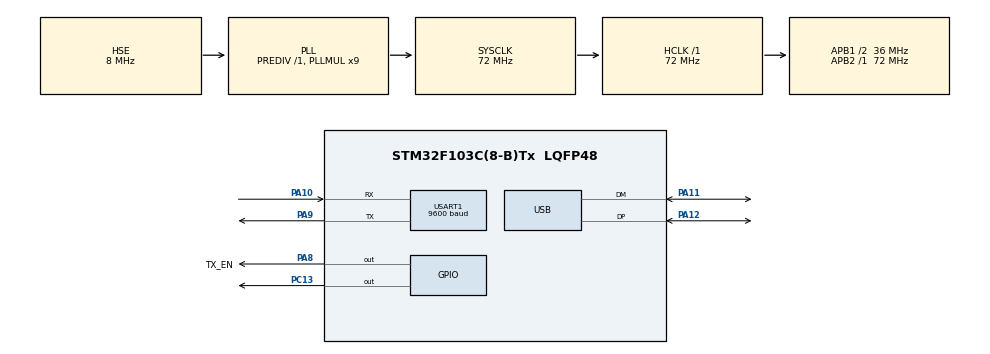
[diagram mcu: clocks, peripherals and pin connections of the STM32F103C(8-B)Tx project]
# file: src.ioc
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Mcu.Family=STM32F1
Mcu.Name=STM32F103C(8-B)Tx
Mcu.Package=LQFP48
NVIC.PriorityGroup=NVIC_PRIORITYGROUP_4
NVIC.USART1_IRQn=true\:0\:0\:false\:false\:true\:true\:true\:true
NVIC.USB_LP_CAN1_RX0_IRQn=true\:0\:0\:false\:false\:true\:false\:true\:true
PA10.Mode=Asynchronous
PA10.Signal=USART1_RX
PA11.Mode=Device
PA11.Signal=USB_DM
PA12.Mode=Device
PA12.Signal=USB_DP
PA13.Mode=Serial_Wire
PA13.Signal=SYS_JTMS-SWDIO
PA14.Mode=Serial_Wire
PA14.Signal=SYS_JTCK-SWCLK
PA8.GPIO_Label=TX_EN
PA8.Signal=GPIO_Output
PA9.Mode=Asynchronous
PA9.Signal=USART1_TX
PC13-TAMPER-RTC.Signal=GPIO_Output
PD0-OSC_IN.Mode=HSE-External-Oscillator
PD0-OSC_IN.Signal=RCC_OSC_IN
PD1-OSC_OUT.Mode=HSE-External-Oscillator
PD1-OSC_OUT.Signal=RCC_OSC_OUT
ProjectManager.HeapSize=0x200
ProjectManager.StackSize=0x400
ProjectManager.TargetToolchain=EWARM V8.32
RCC.AHBFreq_Value=72000000
RCC.APB1CLKDivider=RCC_HCLK_DIV2
RCC.APB1Freq_Value=36000000
RCC.APB1TimFreq_Value=72000000
RCC.APB2Freq_Value=72000000
RCC.APB2TimFreq_Value=72000000
RCC.HCLKFreq_Value=72000000
RCC.PLLMUL=RCC_PLL_MUL9
RCC.SYSCLKFreq_VALUE=72000000
RCC.SYSCLKSource=RCC_SYSCLKSOURCE_PLLCLK
RCC.USBFreq_Value=48000000
RCC.USBPrescaler=RCC_USBCLKSOURCE_PLL_DIV1_5
USART1.BaudRate=9600
USART1.VirtualMode=VM_ASYNC
USB_DEVICE.CLASS_NAME_FS=CDC
USB_DEVICE.VirtualMode=Cdc
USB_DEVICE.VirtualModeFS=Cdc_FS
VP_USB_DEVICE_VS_USB_DEVICE_CDC_FS.Mode=CDC_FS
board=custom

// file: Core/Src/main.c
/* USER CODE BEGIN Header */
/**
  ******************************************************************************
  * @file           : main.c
  * @brief          : Main program body
  ******************************************************************************
  * @attention
  *
  * Copyright (c) 2022 STMicroelectronics.
  * All rights reserved.
  *
  * This software is licensed under terms that can be found in the LICENSE file
  * in the root directory of this software component.
  * If no LICENSE file comes with this software, it is provided  AS-IS.
  *
  ******************************************************************************
  */
/* USER CODE END Header */
#include "main.h"
#include "usb_device.h"
/* USER CODE BEGIN Includes */
#include "usbd_core.h"
#include "usbd_cdc_if.h"
#include "modbus_crc.h"
#include "mbus_funcs.h"
/* USER CODE END Includes */

UART_HandleTypeDef huart1;

/* USER CODE BEGIN 0 */
void SystemClock_Config(void);
static void MX_GPIO_Init(void);
static void MX_USART1_UART_Init(void);
extern USBD_HandleTypeDef hUsbDeviceFS;

/* USER CODE END 0 */

int main(void)
{

  /* MCU Configuration--------------------------------------------------------*/

  /* Reset of all peripherals, Initializes the Flash interface and the Systick. */
  HAL_Init();

  /* Configure the system clock */
  SystemClock_Config();

  /* Initialize all configured peripherals */
  MX_GPIO_Init();
  MX_USB_DEVICE_Init();
  MX_USART1_UART_Init();
  /* USER CODE BEGIN 2 */

//Funciones ejemplo ModBUS

//readCoils(address, posicion, cantidad de coils);
  //readCoils(0x0001, 0, 1); // Example: Read 1 coils starting from position 0 of slave with address 1

//writeSingleCoil(address, posicion, valor);
  //writeSingleCoil(0x0001, 0, 1); // Example: Write value 1 (ON) to coil at position 0 of slave with address 1

//readInputContacts(address, posicion, cantidad de contactos);
  //readInputContacts(0x0001, 0, 10); // Example: Read 10 input contacts starting from position 0 of slave with address 1

//writeSingleRegister(address, posicion, valor);
  //writeSingleRegister(0x0001, 0, 123); // Example: Write value 123 to register at position 0 of slave with address 1

//writeMultipleRegisters(address, posicion, *datos, cantidad de datos);
//uint16_t datos[2] = {123, 456};
//writeMultipleRegisters(0x0001, 3, datos, 2);

//readHoldingRegisters(address, posicion, cantidad de datos);
  readHoldingRegisters(0x0001, 3, 2); // Example: Read registers at positions 6 and 7 of slave with address 1
  //readAnalogInputs(address, posicion, cantidad de datos);
  //readAnalogInputs(0x0001, 0, 2); // Example: Read analog inputs at positions 0 and 1 of slave with address 1

  /* USER CODE END 2 */

  /* Infinite loop */
  /* USER CODE BEGIN WHILE */
  while (1)
  {
    /* Button detection: PA0 press triggers Modbus read without reset */
    static uint8_t last_btn = 0;
    uint8_t btn = (HAL_GPIO_ReadPin(GPIOB, GPIO_PIN_10) == GPIO_PIN_SET) ? 1 : 0;
    if (btn && !last_btn) {
      HAL_Delay(20); /* debounce */
      if (HAL_GPIO_ReadPin(GPIOB, GPIO_PIN_10) == GPIO_PIN_SET) {
        readHoldingRegisters(0x0001, 3, 2);
      }
    }
    last_btn = btn;

    /* If UART callback marked data ready, try sending over USB when configured. */
    if (usb_data_ready)
    {
      if (hUsbDeviceFS.dev_state == USBD_STATE_CONFIGURED)
      {
        if (usb_buffer_len < sizeof(usb_buffer))
        {
          usb_buffer[usb_buffer_len++] = '\n';
        }

        uint8_t res = CDC_Transmit_FS(usb_buffer, usb_buffer_len);
        if (res == USBD_OK)
        {
          usb_data_ready = 0; // sent
        }
        else if (res == USBD_BUSY)
        {
          /* Host busy — keep flag set and retry next loop */
        }
        else
        {
          /* On error, drop the data to avoid lock — you can implement retries */
          usb_data_ready = 0;
        }
      }
    }

    HAL_Delay(10);
  }

    /* USER CODE END WHILE */

  /* USER CODE END 3 */
}

void SystemClock_Config(void)
{
  RCC_OscInitTypeDef RCC_OscInitStruct = {0};
  RCC_ClkInitTypeDef RCC_ClkInitStruct = {0};
  RCC_PeriphCLKInitTypeDef PeriphClkInit = {0};

  /** Initializes the RCC Oscillators according to the specified parameters
  * in the RCC_OscInitTypeDef structure.
  */
  RCC_OscInitStruct.OscillatorType = RCC_OSCILLATORTYPE_HSE;
  RCC_OscInitStruct.HSEState = RCC_HSE_ON;
  RCC_OscInitStruct.HSEPredivValue = RCC_HSE_PREDIV_DIV1;
  RCC_OscInitStruct.HSIState = RCC_HSI_ON;
  RCC_OscInitStruct.PLL.PLLState = RCC_PLL_ON;
  RCC_OscInitStruct.PLL.PLLSource = RCC_PLLSOURCE_HSE;
  RCC_OscInitStruct.PLL.PLLMUL = RCC_PLL_MUL9;
  if (HAL_RCC_OscConfig(&RCC_OscInitStruct) != HAL_OK)
  {
    Error_Handler();
  }

  /** Initializes the CPU, AHB and APB buses clocks
  */
  RCC_ClkInitStruct.ClockType = RCC_CLOCKTYPE_HCLK|RCC_CLOCKTYPE_SYSCLK
                              |RCC_CLOCKTYPE_PCLK1|RCC_CLOCKTYPE_PCLK2;
  RCC_ClkInitStruct.SYSCLKSource = RCC_SYSCLKSOURCE_PLLCLK;
  RCC_ClkInitStruct.AHBCLKDivider = RCC_SYSCLK_DIV1;
  RCC_ClkInitStruct.APB1CLKDivider = RCC_HCLK_DIV2;
  RCC_ClkInitStruct.APB2CLKDivider = RCC_HCLK_DIV1;

  if (HAL_RCC_ClockConfig(&RCC_ClkInitStruct, FLASH_LATENCY_2) != HAL_OK)
  {
    Error_Handler();
  }
  PeriphClkInit.PeriphClockSelection = RCC_PERIPHCLK_USB;
  PeriphClkInit.UsbClockSelection = RCC_USBCLKSOURCE_PLL_DIV1_5;
  if (HAL_RCCEx_PeriphCLKConfig(&PeriphClkInit) != HAL_OK)
  {
    Error_Handler();
  }
}

static void MX_USART1_UART_Init(void)
{

  huart1.Instance = USART1;
  huart1.Init.BaudRate = 9600;
  huart1.Init.WordLength = UART_WORDLENGTH_8B;
  huart1.Init.StopBits = UART_STOPBITS_1;
  huart1.Init.Parity = UART_PARITY_NONE;
  huart1.Init.Mode = UART_MODE_TX_RX;
  huart1.Init.HwFlowCtl = UART_HWCONTROL_NONE;
  huart1.Init.OverSampling = UART_OVERSAMPLING_16;
  if (HAL_UART_Init(&huart1) != HAL_OK)
  {
    Error_Handler();
  }

}

static void MX_GPIO_Init(void)
{
  GPIO_InitTypeDef GPIO_InitStruct = {0};

  /* GPIO Ports Clock Enable */
  __HAL_RCC_GPIOA_CLK_ENABLE();
  __HAL_RCC_GPIOB_CLK_ENABLE();
  __HAL_RCC_GPIOC_CLK_ENABLE();
  __HAL_RCC_GPIOD_CLK_ENABLE();

  /*Configure GPIO pin Output Level */
  HAL_GPIO_WritePin(GPIOC, GPIO_PIN_13, GPIO_PIN_RESET);

  /*Configure GPIO pin Output Level */
  HAL_GPIO_WritePin(TX_EN_GPIO_Port, TX_EN_Pin, GPIO_PIN_RESET);

  /*Configure GPIO pin : PA1 (button input) */
  GPIO_InitStruct.Pin = GPIO_PIN_1;
  GPIO_InitStruct.Mode = GPIO_MODE_INPUT;
  GPIO_InitStruct.Pull = GPIO_PULLDOWN;
  HAL_GPIO_Init(GPIOA, &GPIO_InitStruct);

  /*Configure GPIO pin : PC13 */
  GPIO_InitStruct.Pin = GPIO_PIN_13;
  GPIO_InitStruct.Mode = GPIO_MODE_OUTPUT_PP;
  GPIO_InitStruct.Pull = GPIO_NOPULL;
  GPIO_InitStruct.Speed = GPIO_SPEED_FREQ_LOW;
  HAL_GPIO_Init(GPIOC, &GPIO_InitStruct);

  /*Configure GPIO pin : TX_EN_Pin */
  GPIO_InitStruct.Pin = TX_EN_Pin;
  GPIO_InitStruct.Mode = GPIO_MODE_OUTPUT_PP;
  GPIO_InitStruct.Pull = GPIO_NOPULL;
  GPIO_InitStruct.Speed = GPIO_SPEED_FREQ_LOW;
  HAL_GPIO_Init(TX_EN_GPIO_Port, &GPIO_InitStruct);

  GPIO_InitStruct.Pin = GPIO_PIN_10;
  GPIO_InitStruct.Mode = GPIO_MODE_INPUT;
  GPIO_InitStruct.Pull = GPIO_PULLDOWN;
  HAL_GPIO_Init(GPIOB, &GPIO_InitStruct);
}

void Error_Handler(void)
{
  __disable_irq();
  while (1)
  {
  }
}
